VERSION 5.7 ;
BUSBITCHARS "[]" ;
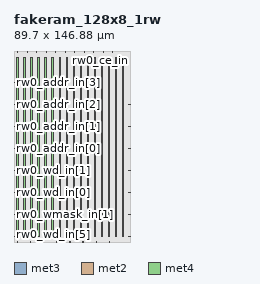
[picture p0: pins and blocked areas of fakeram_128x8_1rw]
MACRO fakeram_128x8_1rw
  FOREIGN fakeram_128x8_1rw 0 0 ;
  SYMMETRY X Y R90 ;
  SIZE 89.700 BY 146.880 ;
  CLASS BLOCK ;
  PIN rw0_wmask_in[0]
    DIRECTION INPUT ;
    USE SIGNAL ;
    SHAPE ABUTMENT ;
    PORT
      LAYER met3 ;
      RECT 0.000 3.930 0.900 4.230 ;
    END
  END rw0_wmask_in[0]
  PIN rw0_wmask_in[1]
    DIRECTION INPUT ;
    USE SIGNAL ;
    SHAPE ABUTMENT ;
    PORT
      LAYER met3 ;
      RECT 0.000 20.930 0.900 21.230 ;
    END
  END rw0_wmask_in[1]
  PIN rw0_wmask_in[2]
    DIRECTION INPUT ;
    USE SIGNAL ;
    SHAPE ABUTMENT ;
    PORT
      LAYER met3 ;
      RECT 88.800 3.930 89.700 4.230 ;
    END
  END rw0_wmask_in[2]
  PIN rw0_wmask_in[3]
    DIRECTION INPUT ;
    USE SIGNAL ;
    SHAPE ABUTMENT ;
    PORT
      LAYER met3 ;
      RECT 88.800 20.930 89.700 21.230 ;
    END
  END rw0_wmask_in[3]
  PIN rw0_wmask_in[4]
    DIRECTION INPUT ;
    USE SIGNAL ;
    SHAPE ABUTMENT ;
    PORT
      LAYER met2 ;
      RECT 2.690 146.460 2.830 146.880 ;
    END
  END rw0_wmask_in[4]
  PIN rw0_wmask_in[5]
    DIRECTION INPUT ;
    USE SIGNAL ;
    SHAPE ABUTMENT ;
    PORT
      LAYER met2 ;
      RECT 10.050 146.460 10.190 146.880 ;
    END
  END rw0_wmask_in[5]
  PIN rw0_wmask_in[6]
    DIRECTION INPUT ;
    USE SIGNAL ;
    SHAPE ABUTMENT ;
    PORT
      LAYER met2 ;
      RECT 17.410 146.460 17.550 146.880 ;
    END
  END rw0_wmask_in[6]
  PIN rw0_wmask_in[7]
    DIRECTION INPUT ;
    USE SIGNAL ;
    SHAPE ABUTMENT ;
    PORT
      LAYER met2 ;
      RECT 24.770 146.460 24.910 146.880 ;
    END
  END rw0_wmask_in[7]
  PIN rw0_wd_in[0]
    DIRECTION INPUT ;
    USE SIGNAL ;
    SHAPE ABUTMENT ;
    PORT
      LAYER met3 ;
      RECT 0.000 37.930 0.900 38.230 ;
    END
  END rw0_wd_in[0]
  PIN rw0_wd_in[1]
    DIRECTION INPUT ;
    USE SIGNAL ;
    SHAPE ABUTMENT ;
    PORT
      LAYER met3 ;
      RECT 0.000 54.930 0.900 55.230 ;
    END
  END rw0_wd_in[1]
  PIN rw0_wd_in[2]
    DIRECTION INPUT ;
    USE SIGNAL ;
    SHAPE ABUTMENT ;
    PORT
      LAYER met3 ;
      RECT 88.800 37.930 89.700 38.230 ;
    END
  END rw0_wd_in[2]
  PIN rw0_wd_in[3]
    DIRECTION INPUT ;
    USE SIGNAL ;
    SHAPE ABUTMENT ;
    PORT
      LAYER met3 ;
      RECT 88.800 54.930 89.700 55.230 ;
    END
  END rw0_wd_in[3]
  PIN rw0_wd_in[4]
    DIRECTION INPUT ;
    USE SIGNAL ;
    SHAPE ABUTMENT ;
    PORT
      LAYER met2 ;
      RECT 2.690 0.000 2.830 0.420 ;
    END
  END rw0_wd_in[4]
  PIN rw0_wd_in[5]
    DIRECTION INPUT ;
    USE SIGNAL ;
    SHAPE ABUTMENT ;
    PORT
      LAYER met2 ;
      RECT 12.810 0.000 12.950 0.420 ;
    END
  END rw0_wd_in[5]
  PIN rw0_wd_in[6]
    DIRECTION INPUT ;
    USE SIGNAL ;
    SHAPE ABUTMENT ;
    PORT
      LAYER met2 ;
      RECT 22.930 0.000 23.070 0.420 ;
    END
  END rw0_wd_in[6]
  PIN rw0_wd_in[7]
    DIRECTION INPUT ;
    USE SIGNAL ;
    SHAPE ABUTMENT ;
    PORT
      LAYER met2 ;
      RECT 33.050 0.000 33.190 0.420 ;
    END
  END rw0_wd_in[7]
  PIN rw0_rd_out[0]
    DIRECTION OUTPUT ;
    USE SIGNAL ;
    SHAPE ABUTMENT ;
    PORT
      LAYER met2 ;
      RECT 43.170 0.000 43.310 0.420 ;
    END
  END rw0_rd_out[0]
  PIN rw0_rd_out[1]
    DIRECTION OUTPUT ;
    USE SIGNAL ;
    SHAPE ABUTMENT ;
    PORT
      LAYER met2 ;
      RECT 53.290 0.000 53.430 0.420 ;
    END
  END rw0_rd_out[1]
  PIN rw0_rd_out[2]
    DIRECTION OUTPUT ;
    USE SIGNAL ;
    SHAPE ABUTMENT ;
    PORT
      LAYER met2 ;
      RECT 63.410 0.000 63.550 0.420 ;
    END
  END rw0_rd_out[2]
  PIN rw0_rd_out[3]
    DIRECTION OUTPUT ;
    USE SIGNAL ;
    SHAPE ABUTMENT ;
    PORT
      LAYER met2 ;
      RECT 73.530 0.000 73.670 0.420 ;
    END
  END rw0_rd_out[3]
  PIN rw0_rd_out[4]
    DIRECTION OUTPUT ;
    USE SIGNAL ;
    SHAPE ABUTMENT ;
    PORT
      LAYER met2 ;
      RECT 32.130 146.460 32.270 146.880 ;
    END
  END rw0_rd_out[4]
  PIN rw0_rd_out[5]
    DIRECTION OUTPUT ;
    USE SIGNAL ;
    SHAPE ABUTMENT ;
    PORT
      LAYER met2 ;
      RECT 39.490 146.460 39.630 146.880 ;
    END
  END rw0_rd_out[5]
  PIN rw0_rd_out[6]
    DIRECTION OUTPUT ;
    USE SIGNAL ;
    SHAPE ABUTMENT ;
    PORT
      LAYER met2 ;
      RECT 46.850 146.460 46.990 146.880 ;
    END
  END rw0_rd_out[6]
  PIN rw0_rd_out[7]
    DIRECTION OUTPUT ;
    USE SIGNAL ;
    SHAPE ABUTMENT ;
    PORT
      LAYER met2 ;
      RECT 54.210 146.460 54.350 146.880 ;
    END
  END rw0_rd_out[7]
  PIN rw0_addr_in[0]
    DIRECTION INPUT ;
    USE SIGNAL ;
    SHAPE ABUTMENT ;
    PORT
      LAYER met3 ;
      RECT 0.000 71.930 0.900 72.230 ;
    END
  END rw0_addr_in[0]
  PIN rw0_addr_in[1]
    DIRECTION INPUT ;
    USE SIGNAL ;
    SHAPE ABUTMENT ;
    PORT
      LAYER met3 ;
      RECT 0.000 88.930 0.900 89.230 ;
    END
  END rw0_addr_in[1]
  PIN rw0_addr_in[2]
    DIRECTION INPUT ;
    USE SIGNAL ;
    SHAPE ABUTMENT ;
    PORT
      LAYER met3 ;
      RECT 0.000 105.930 0.900 106.230 ;
    END
  END rw0_addr_in[2]
  PIN rw0_addr_in[3]
    DIRECTION INPUT ;
    USE SIGNAL ;
    SHAPE ABUTMENT ;
    PORT
      LAYER met3 ;
      RECT 0.000 122.930 0.900 123.230 ;
    END
  END rw0_addr_in[3]
  PIN rw0_addr_in[4]
    DIRECTION INPUT ;
    USE SIGNAL ;
    SHAPE ABUTMENT ;
    PORT
      LAYER met3 ;
      RECT 88.800 71.930 89.700 72.230 ;
    END
  END rw0_addr_in[4]
  PIN rw0_addr_in[5]
    DIRECTION INPUT ;
    USE SIGNAL ;
    SHAPE ABUTMENT ;
    PORT
      LAYER met3 ;
      RECT 88.800 88.930 89.700 89.230 ;
    END
  END rw0_addr_in[5]
  PIN rw0_addr_in[6]
    DIRECTION INPUT ;
    USE SIGNAL ;
    SHAPE ABUTMENT ;
    PORT
      LAYER met3 ;
      RECT 88.800 105.930 89.700 106.230 ;
    END
  END rw0_addr_in[6]
  PIN rw0_we_in
    DIRECTION INPUT ;
    USE SIGNAL ;
    SHAPE ABUTMENT ;
    PORT
      LAYER met2 ;
      RECT 61.570 146.460 61.710 146.880 ;
    END
  END rw0_we_in
  PIN rw0_ce_in
    DIRECTION INPUT ;
    USE SIGNAL ;
    SHAPE ABUTMENT ;
    PORT
      LAYER met2 ;
      RECT 68.930 146.460 69.070 146.880 ;
    END
  END rw0_ce_in
  PIN rw0_clk
    DIRECTION INPUT ;
    USE SIGNAL ;
    SHAPE ABUTMENT ;
    PORT
      LAYER met2 ;
      RECT 76.290 146.460 76.430 146.880 ;
    END
  END rw0_clk
  PIN VSS
    DIRECTION INOUT ;
    USE GROUND ;
    PORT
      LAYER met4 ;
      RECT 2.160 4.080 3.360 142.800 ;
      RECT 13.040 4.080 14.240 142.800 ;
      RECT 23.920 4.080 25.120 142.800 ;
      RECT 34.800 4.080 36.000 142.800 ;
      RECT 45.680 4.080 46.880 142.800 ;
      RECT 56.560 4.080 57.760 142.800 ;
      RECT 67.440 4.080 68.640 142.800 ;
      RECT 78.320 4.080 79.520 142.800 ;
    END
  END VSS
  PIN VDD
    DIRECTION INOUT ;
    USE POWER ;
    PORT
      LAYER met4 ;
      RECT 7.600 4.080 8.800 142.800 ;
      RECT 18.480 4.080 19.680 142.800 ;
      RECT 29.360 4.080 30.560 142.800 ;
      RECT 40.240 4.080 41.440 142.800 ;
      RECT 51.120 4.080 52.320 142.800 ;
      RECT 62.000 4.080 63.200 142.800 ;
      RECT 72.880 4.080 74.080 142.800 ;
      RECT 83.760 4.080 84.960 142.800 ;
    END
  END VDD
  OBS
    LAYER met1 ;
    RECT 0 0 89.700 146.880 ;
    LAYER met2 ;
    RECT 0 0 89.700 146.880 ;
    LAYER met3 ;
    RECT 0 0 89.700 146.880 ;
    LAYER met4 ;
    RECT 0 0 89.700 146.880 ;
  END
END fakeram_128x8_1rw

END LIBRARY
